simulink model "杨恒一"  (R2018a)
settings: Solver=VariableStepAuto  StartTime=0.0  StopTime=2  RelTol=1e-3
libraries: simulink x1

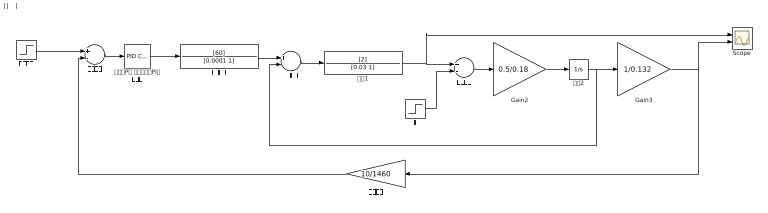
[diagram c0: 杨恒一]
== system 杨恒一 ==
  Gain2 : Gain  Gain=0.5/0.18
  Gain3 : Gain  Gain=1/0.132
  Scope : Scope  NumInputPorts=2
  反馈系数 : Gain  Gain=10/1460
  比例（P） 比例积分（PI） 控制器 : simulink/Continuous/PID Controller  Controller=P  TimeDomain=Continuous-time  SampleTime=-1  IntegratorMethod=Forward Euler  FilterMethod=Forward Euler  Form=Parallel  UseFilter=on  ControllerParametersSource=internal  P=30  I=10  D=0  N=100  InitialConditionSource=internal  InitialConditionForIntegrator=0  InitialConditionForFilter=0  ExternalReset=none  LimitOutput=off  UpperSaturationLimit=inf  LowerSaturationLimit=-inf  LinearizeAsGain=on  AntiWindupMode=none  Kb=1  TrackingMode=off  Kt=1  PParamMin=[]  PParamMax=[]  IParamMin=[]  IParamMax=[]  DParamMin=[]  DParamMax=[]  NParamMin=[]  NParamMax=[]  KbParamMin=[]  KbParamMax=[]  KtParamMin=[]  KtParamMax=[]  POutMin=[]  POutMax=[]  IOutMin=[]  IOutMax=[]  DOutMin=[]  DOutMax=[]  NOutMin=[]  NOutMax=[]  KbOutMin=[]  KbOutMax=[]  KtOutMin=[]  KtOutMax=[]  IntegratorOutMin=[]  IntegratorOutMax=[]  FilterOutMin=[]  FilterOutMax=[]  SumOutMin=[]  SumOutMax=[]  SumI1OutMin=[]  SumI1OutMax=[]  SumI2OutMin=[]  SumI2OutMax=[]  SumI3OutMin=[]  SumI3OutMax=[]  SumDOutMin=[]  SumDOutMax=[]  SaturationOutMin=[]  SaturationOutMax=[]  IntegratorContinuousStateAttributes=''  IntegratorStateMustResolveToSignalObject=off  IntegratorRTWStateStorageClass=Auto  FilterContinuousStateAttributes=''  FilterStateMustResolveToSignalObject=off  FilterRTWStateStorageClass=Auto  DifferentiatorICPrevScaledInput=0  DifferentiatorOutMin=[]  DifferentiatorOutMax=[]  FilterDiffOutCoefMin=[]  FilterDiffOutCoefMax=[]  SumDenOutMin=[]  SumDenOutMax=[]  SumNumOutMin=[]  SumNumOutMax=[]  ReciprocalOutMin=[]  ReciprocalOutMax=[]  DivideOutMin=[]  DivideOutMax=[]  TunerSelectOption=Transfer Function Based (PID Tuner App)
  比较转速 : Sum  Inputs=+-
  电压比较 : Sum  Inputs=+-
  电机1 : TransferFcn  Numerator=[2]  Denominator=[0.03 1]
  电机2 : Integrator
  电流比较 : Sum  Inputs=+-
  给定转速 : TransferFcn  Numerator=[60]  Denominator=[0.0001 1]
  负载 : Step  After=100  SampleTime=0
  转速给定 : Step  Time=0  After=10  SampleTime=0
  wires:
  转速给定/1 -> 比较转速/1
  电压比较/1 -> 电机1/1
  电机1/1 -> Scope/1, 电流比较/1
  负载/1 -> 电流比较/2
  电流比较/1 -> Gain2/1
  Gain2/1 -> 电机2/1
  电机2/1 -> 电压比较/2, Gain3/1
  Gain3/1 -> Scope/2, 反馈系数/1
  给定转速/1 -> 电压比较/1
  反馈系数/1 -> 比较转速/2
  比较转速/1 -> 比例（P） 比例积分（PI） 控制器/1
  比例（P） 比例积分（PI） 控制器/1 -> 给定转速/1
